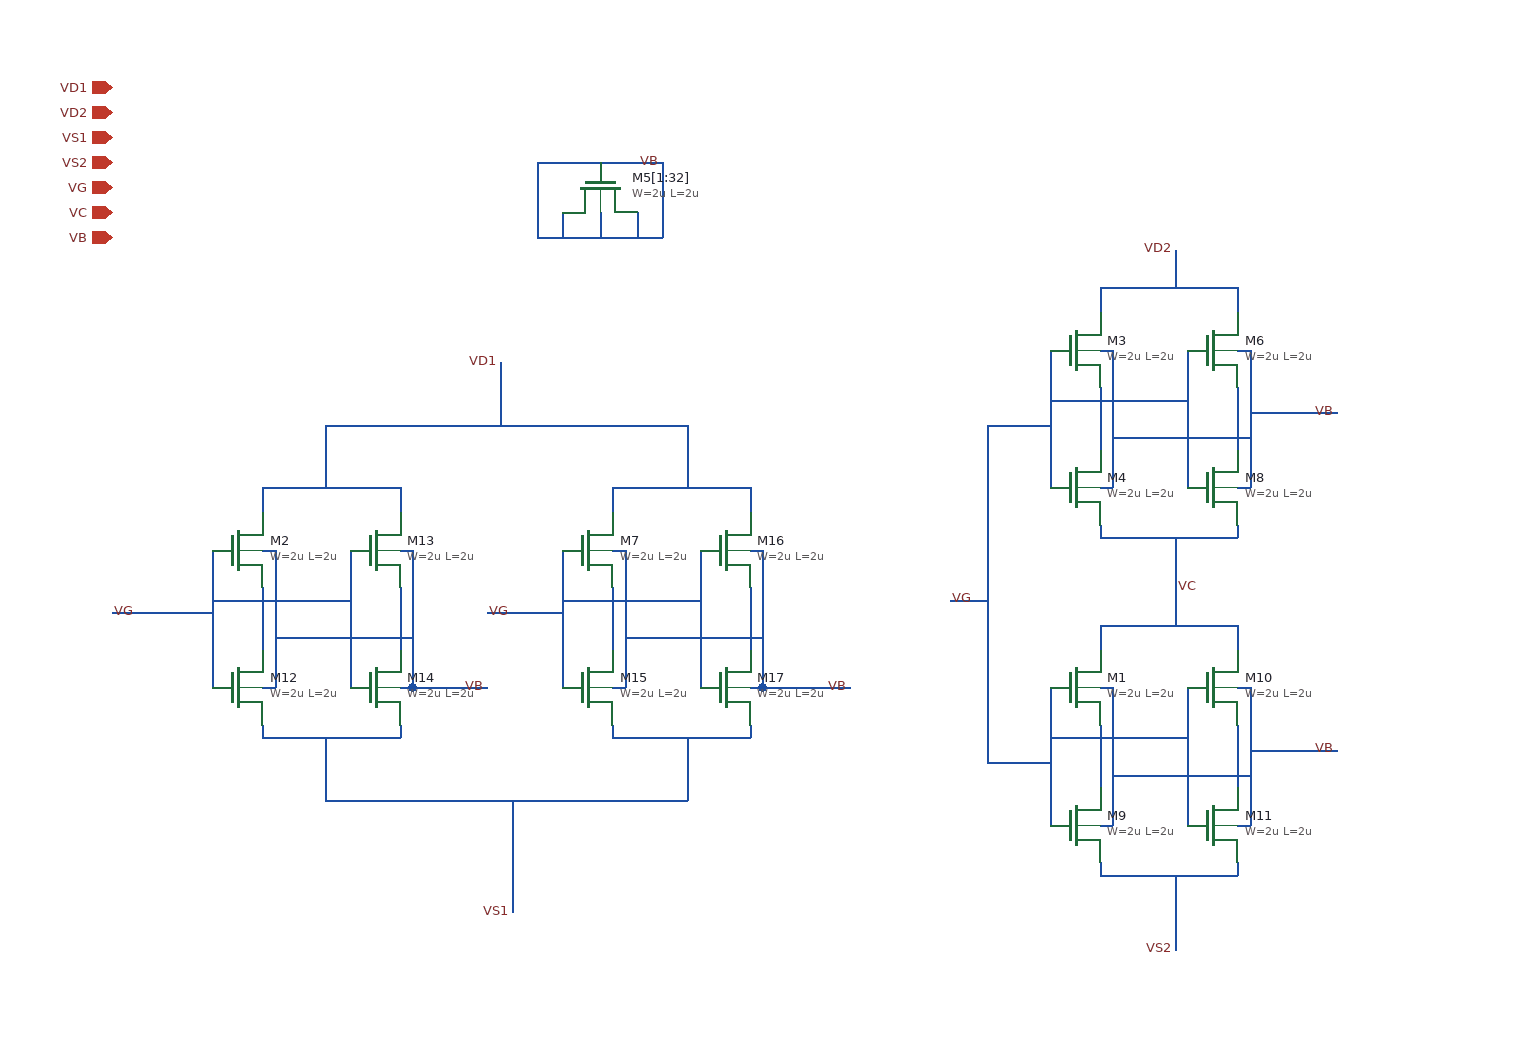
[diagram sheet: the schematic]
v {xschem version=3.4.5 file_version=1.2
}
G {}
K {}
V {}
S {}
E {}
N 100 -300 150 -300 {
lab=VB}
N 100 -300 100 -240 {
lab=VB}
N 100 -240 200 -240 {
lab=VB}
N 200 -300 200 -240 {
lab=VB}
N 150 -300 200 -300 {
lab=VB}
N 180 -260 180 -240 {
lab=VB}
N 150 -260 150 -240 {
lab=VB}
N 120 -260 120 -240 {
lab=VB}
N 550 -120 550 -70 {
lab=#net1}
N 660 -120 660 -70 {
lab=#net2}
N 510 -150 510 -40 {
lab=VG}
N 660 -150 670 -150 {
lab=VBpr}
N 670 -150 670 -40 {
lab=VBpr}
N 660 -40 670 -40 {
lab=VBpr}
N 550 -150 560 -150 {
lab=VBpr}
N 560 -150 560 -40 {
lab=VBpr}
N 550 -40 560 -40 {
lab=VBpr}
N 620 -150 620 -40 {
lab=VG}
N 510 -110 620 -110 {
lab=VG}
N 560 -80 670 -80 {
lab=VBpr}
N 670 -100 740 -100 {
lab=VBpr}
N 550 -200 550 -180 {
lab=VD2}
N 550 -200 660 -200 {
lab=VD2}
N 660 -200 660 -180 {
lab=VD2}
N 610 -220 610 -200 {
lab=VD2}
N 550 -10 550 0 {
lab=VC}
N 550 0 660 0 {
lab=VC}
N 660 -10 660 0 {
lab=VC}
N 610 0 610 40 {
lab=VC}
N 460 -90 510 -90 {
lab=VG}
N 610 -230 610 -220 {
lab=VD2}
N 550 150 550 200 {
lab=#net3}
N 660 150 660 200 {
lab=#net4}
N 510 120 510 230 {
lab=VG}
N 660 120 670 120 {
lab=VBpr}
N 670 120 670 230 {
lab=VBpr}
N 660 230 670 230 {
lab=VBpr}
N 550 120 560 120 {
lab=VBpr}
N 560 120 560 230 {
lab=VBpr}
N 550 230 560 230 {
lab=VBpr}
N 620 120 620 230 {
lab=VG}
N 510 160 620 160 {
lab=VG}
N 560 190 670 190 {
lab=VBpr}
N 670 170 740 170 {
lab=VBpr}
N 550 70 550 90 {
lab=VC}
N 550 70 660 70 {
lab=VC}
N 660 70 660 90 {
lab=VC}
N 610 50 610 70 {
lab=VC}
N 550 260 550 270 {
lab=VS2}
N 550 270 660 270 {
lab=VS2}
N 660 260 660 270 {
lab=VS2}
N 460 180 510 180 {
lab=VG}
N 610 40 610 50 {
lab=VC}
N 610 270 610 330 {
lab=VS2}
N 460 -90 460 180 {
lab=VG}
N 440 50 460 50 {
lab=VG}
N -120 40 -120 90 {
lab=#net5}
N -10 40 -10 90 {
lab=#net6}
N -160 10 -160 120 {
lab=VG}
N -10 10 0 10 {
lab=VB}
N 0 10 0 120 {
lab=VB}
N -10 120 0 120 {
lab=VB}
N -120 10 -110 10 {
lab=VB}
N -110 10 -110 120 {
lab=VB}
N -120 120 -110 120 {
lab=VB}
N -50 10 -50 120 {
lab=VG}
N -160 50 -50 50 {
lab=VG}
N -110 80 0 80 {
lab=VB}
N -120 -40 -120 -20 {
lab=VD1}
N -120 -40 -10 -40 {
lab=VD1}
N -10 -40 -10 -20 {
lab=VD1}
N -120 150 -120 160 {
lab=VS1}
N -120 160 -10 160 {
lab=VS1}
N -10 150 -10 160 {
lab=VS1}
N 160 40 160 90 {
lab=#net7}
N 270 40 270 90 {
lab=#net8}
N 120 10 120 120 {
lab=VG}
N 270 10 280 10 {
lab=VB}
N 280 10 280 120 {
lab=VB}
N 270 120 280 120 {
lab=VB}
N 160 10 170 10 {
lab=VB}
N 170 10 170 120 {
lab=VB}
N 160 120 170 120 {
lab=VB}
N 230 10 230 120 {
lab=VG}
N 120 50 230 50 {
lab=VG}
N 170 80 280 80 {
lab=VB}
N 160 -40 160 -20 {
lab=VD1}
N 160 -40 270 -40 {
lab=VD1}
N 270 -40 270 -20 {
lab=VD1}
N 220 -60 220 -40 {
lab=VD1}
N 160 150 160 160 {
lab=VS1}
N 160 160 270 160 {
lab=VS1}
N 270 150 270 160 {
lab=VS1}
N 220 -70 220 -60 {
lab=VD1}
N -70 -90 -70 -40 {
lab=VD1}
N 220 -90 220 -70 {
lab=VD1}
N -70 -90 210 -90 {
lab=VD1}
N 210 -90 220 -90 {
lab=VD1}
N 70 -140 70 -90 {
lab=VD1}
N -240 60 -160 60 {
lab=VG}
N 0 120 60 120 {
lab=VB}
N 280 120 350 120 {
lab=VB}
N 60 60 120 60 {
lab=VG}
N -70 160 -70 210 {
lab=VS1}
N -70 210 220 210 {
lab=VS1}
N 220 160 220 210 {
lab=VS1}
N 80 210 80 280 {
lab=VS1}
N 80 280 80 300 {
lab=VS1}
N 430 50 440 50 {
lab=VG}
C {symbols/nfet_03v3.sym} 150 -280 3 1 {name=M5[1:32]
L=2u
W=2u
nf=1
m=1
ad="'int((nf+1)/2) * W/nf * 0.18u'"
pd="'2*int((nf+1)/2) * (W/nf + 0.18u)'"
as="'int((nf+2)/2) * W/nf * 0.18u'"
ps="'2*int((nf+2)/2) * (W/nf + 0.18u)'"
nrd="'0.18u / W'" nrs="'0.18u / W'"
sa=0 sb=0 sd=0
model=nfet_03v3
spiceprefix=X
}
C {symbols/nfet_03v3.sym} 530 -150 0 0 {name=M3
L=2u
W=2u
nf=1
m=1
ad="'int((nf+1)/2) * W/nf * 0.18u'"
pd="'2*int((nf+1)/2) * (W/nf + 0.18u)'"
as="'int((nf+2)/2) * W/nf * 0.18u'"
ps="'2*int((nf+2)/2) * (W/nf + 0.18u)'"
nrd="'0.18u / W'" nrs="'0.18u / W'"
sa=0 sb=0 sd=0
model=nfet_03v3
spiceprefix=X
}
C {symbols/nfet_03v3.sym} 530 -40 0 0 {name=M4
L=2u
W=2u
nf=1
m=1
ad="'int((nf+1)/2) * W/nf * 0.18u'"
pd="'2*int((nf+1)/2) * (W/nf + 0.18u)'"
as="'int((nf+2)/2) * W/nf * 0.18u'"
ps="'2*int((nf+2)/2) * (W/nf + 0.18u)'"
nrd="'0.18u / W'" nrs="'0.18u / W'"
sa=0 sb=0 sd=0
model=nfet_03v3
spiceprefix=X
}
C {symbols/nfet_03v3.sym} 640 -150 0 0 {name=M6
L=2u
W=2u
nf=1
m=1
ad="'int((nf+1)/2) * W/nf * 0.18u'"
pd="'2*int((nf+1)/2) * (W/nf + 0.18u)'"
as="'int((nf+2)/2) * W/nf * 0.18u'"
ps="'2*int((nf+2)/2) * (W/nf + 0.18u)'"
nrd="'0.18u / W'" nrs="'0.18u / W'"
sa=0 sb=0 sd=0
model=nfet_03v3
spiceprefix=X
}
C {symbols/nfet_03v3.sym} 640 -40 0 0 {name=M8
L=2u
W=2u
nf=1
m=1
ad="'int((nf+1)/2) * W/nf * 0.18u'"
pd="'2*int((nf+1)/2) * (W/nf + 0.18u)'"
as="'int((nf+2)/2) * W/nf * 0.18u'"
ps="'2*int((nf+2)/2) * (W/nf + 0.18u)'"
nrd="'0.18u / W'" nrs="'0.18u / W'"
sa=0 sb=0 sd=0
model=nfet_03v3
spiceprefix=X
}
C {symbols/nfet_03v3.sym} 530 120 0 0 {name=M1
L=2u
W=2u
nf=1
m=1
ad="'int((nf+1)/2) * W/nf * 0.18u'"
pd="'2*int((nf+1)/2) * (W/nf + 0.18u)'"
as="'int((nf+2)/2) * W/nf * 0.18u'"
ps="'2*int((nf+2)/2) * (W/nf + 0.18u)'"
nrd="'0.18u / W'" nrs="'0.18u / W'"
sa=0 sb=0 sd=0
model=nfet_03v3
spiceprefix=X
}
C {symbols/nfet_03v3.sym} 530 230 0 0 {name=M9
L=2u
W=2u
nf=1
m=1
ad="'int((nf+1)/2) * W/nf * 0.18u'"
pd="'2*int((nf+1)/2) * (W/nf + 0.18u)'"
as="'int((nf+2)/2) * W/nf * 0.18u'"
ps="'2*int((nf+2)/2) * (W/nf + 0.18u)'"
nrd="'0.18u / W'" nrs="'0.18u / W'"
sa=0 sb=0 sd=0
model=nfet_03v3
spiceprefix=X
}
C {symbols/nfet_03v3.sym} 640 120 0 0 {name=M10
L=2u
W=2u
nf=1
m=1
ad="'int((nf+1)/2) * W/nf * 0.18u'"
pd="'2*int((nf+1)/2) * (W/nf + 0.18u)'"
as="'int((nf+2)/2) * W/nf * 0.18u'"
ps="'2*int((nf+2)/2) * (W/nf + 0.18u)'"
nrd="'0.18u / W'" nrs="'0.18u / W'"
sa=0 sb=0 sd=0
model=nfet_03v3
spiceprefix=X
}
C {symbols/nfet_03v3.sym} 640 230 0 0 {name=M11
L=2u
W=2u
nf=1
m=1
ad="'int((nf+1)/2) * W/nf * 0.18u'"
pd="'2*int((nf+1)/2) * (W/nf + 0.18u)'"
as="'int((nf+2)/2) * W/nf * 0.18u'"
ps="'2*int((nf+2)/2) * (W/nf + 0.18u)'"
nrd="'0.18u / W'" nrs="'0.18u / W'"
sa=0 sb=0 sd=0
model=nfet_03v3
spiceprefix=X
}
C {symbols/nfet_03v3.sym} -140 10 0 0 {name=M2
L=2u
W=2u
nf=1
m=1
ad="'int((nf+1)/2) * W/nf * 0.18u'"
pd="'2*int((nf+1)/2) * (W/nf + 0.18u)'"
as="'int((nf+2)/2) * W/nf * 0.18u'"
ps="'2*int((nf+2)/2) * (W/nf + 0.18u)'"
nrd="'0.18u / W'" nrs="'0.18u / W'"
sa=0 sb=0 sd=0
model=nfet_03v3
spiceprefix=X
}
C {symbols/nfet_03v3.sym} -140 120 0 0 {name=M12
L=2u
W=2u
nf=1
m=1
ad="'int((nf+1)/2) * W/nf * 0.18u'"
pd="'2*int((nf+1)/2) * (W/nf + 0.18u)'"
as="'int((nf+2)/2) * W/nf * 0.18u'"
ps="'2*int((nf+2)/2) * (W/nf + 0.18u)'"
nrd="'0.18u / W'" nrs="'0.18u / W'"
sa=0 sb=0 sd=0
model=nfet_03v3
spiceprefix=X
}
C {symbols/nfet_03v3.sym} -30 10 0 0 {name=M13
L=2u
W=2u
nf=1
m=1
ad="'int((nf+1)/2) * W/nf * 0.18u'"
pd="'2*int((nf+1)/2) * (W/nf + 0.18u)'"
as="'int((nf+2)/2) * W/nf * 0.18u'"
ps="'2*int((nf+2)/2) * (W/nf + 0.18u)'"
nrd="'0.18u / W'" nrs="'0.18u / W'"
sa=0 sb=0 sd=0
model=nfet_03v3
spiceprefix=X
}
C {symbols/nfet_03v3.sym} -30 120 0 0 {name=M14
L=2u
W=2u
nf=1
m=1
ad="'int((nf+1)/2) * W/nf * 0.18u'"
pd="'2*int((nf+1)/2) * (W/nf + 0.18u)'"
as="'int((nf+2)/2) * W/nf * 0.18u'"
ps="'2*int((nf+2)/2) * (W/nf + 0.18u)'"
nrd="'0.18u / W'" nrs="'0.18u / W'"
sa=0 sb=0 sd=0
model=nfet_03v3
spiceprefix=X
}
C {symbols/nfet_03v3.sym} 140 10 0 0 {name=M7
L=2u
W=2u
nf=1
m=1
ad="'int((nf+1)/2) * W/nf * 0.18u'"
pd="'2*int((nf+1)/2) * (W/nf + 0.18u)'"
as="'int((nf+2)/2) * W/nf * 0.18u'"
ps="'2*int((nf+2)/2) * (W/nf + 0.18u)'"
nrd="'0.18u / W'" nrs="'0.18u / W'"
sa=0 sb=0 sd=0
model=nfet_03v3
spiceprefix=X
}
C {symbols/nfet_03v3.sym} 140 120 0 0 {name=M15
L=2u
W=2u
nf=1
m=1
ad="'int((nf+1)/2) * W/nf * 0.18u'"
pd="'2*int((nf+1)/2) * (W/nf + 0.18u)'"
as="'int((nf+2)/2) * W/nf * 0.18u'"
ps="'2*int((nf+2)/2) * (W/nf + 0.18u)'"
nrd="'0.18u / W'" nrs="'0.18u / W'"
sa=0 sb=0 sd=0
model=nfet_03v3
spiceprefix=X
}
C {symbols/nfet_03v3.sym} 250 10 0 0 {name=M16
L=2u
W=2u
nf=1
m=1
ad="'int((nf+1)/2) * W/nf * 0.18u'"
pd="'2*int((nf+1)/2) * (W/nf + 0.18u)'"
as="'int((nf+2)/2) * W/nf * 0.18u'"
ps="'2*int((nf+2)/2) * (W/nf + 0.18u)'"
nrd="'0.18u / W'" nrs="'0.18u / W'"
sa=0 sb=0 sd=0
model=nfet_03v3
spiceprefix=X
}
C {symbols/nfet_03v3.sym} 250 120 0 0 {name=M17
L=2u
W=2u
nf=1
m=1
ad="'int((nf+1)/2) * W/nf * 0.18u'"
pd="'2*int((nf+1)/2) * (W/nf + 0.18u)'"
as="'int((nf+2)/2) * W/nf * 0.18u'"
ps="'2*int((nf+2)/2) * (W/nf + 0.18u)'"
nrd="'0.18u / W'" nrs="'0.18u / W'"
sa=0 sb=0 sd=0
model=nfet_03v3
spiceprefix=X
}
C {devices/iopin.sym} -240 -360 0 0 {name=p1 lab=VD1}
C {devices/iopin.sym} -240 -340 0 0 {name=p2 lab=VD2}
C {devices/iopin.sym} -240 -320 0 0 {name=p3 lab=VS1}
C {devices/iopin.sym} -240 -300 0 0 {name=p4 lab=VS2}
C {devices/iopin.sym} -240 -280 0 0 {name=p5 lab=VG}
C {devices/iopin.sym} -240 -260 0 0 {name=p6 lab=VC}
C {devices/iopin.sym} -240 -240 0 0 {name=p7 lab=VB}
C {devices/lab_wire.sym} 200 -300 0 0 {name=p8 sig_type=std_logic lab=VB}
C {devices/lab_wire.sym} 60 120 0 0 {name=p9 sig_type=std_logic lab=VB
L=2u
W=2u}
C {devices/lab_wire.sym} 350 120 0 0 {name=p10 sig_type=std_logic lab=VB
L=2u
W=2u}
C {devices/lab_wire.sym} 740 170 0 0 {name=p11 sig_type=std_logic lab=VB
L=2u
W=2u}
C {devices/lab_wire.sym} 740 -100 0 0 {name=p12 sig_type=std_logic lab=VB
L=2u
W=2u}
C {devices/lab_wire.sym} 70 -140 0 0 {name=p13 sig_type=std_logic lab=VD1
L=2u
W=2u}
C {devices/lab_wire.sym} 80 300 0 0 {name=p14 sig_type=std_logic lab=VS1
L=2u
W=2u}
C {devices/lab_wire.sym} 610 -230 0 0 {name=p15 sig_type=std_logic lab=VD2
L=10u
W=1u}
C {devices/lab_wire.sym} 610 330 0 0 {name=p16 sig_type=std_logic lab=VS2
L=10u
W=1u}
C {devices/lab_wire.sym} -220 60 0 0 {name=p17 sig_type=std_logic lab=VG
L=2u
W=2u}
C {devices/lab_wire.sym} 80 60 0 0 {name=p18 sig_type=std_logic lab=VG
L=2u
W=2u}
C {devices/lab_wire.sym} 450 50 0 0 {name=p19 sig_type=std_logic lab=VG
L=2u
W=2u}
C {devices/lab_wire.sym} 610 40 0 1 {name=p20 sig_type=std_logic lab=VC
L=2u
W=2u}
